VERSION 5.7 ;
  NOWIREEXTENSIONATPIN ON ;
  DIVIDERCHAR "/" ;
  BUSBITCHARS "[]" ;
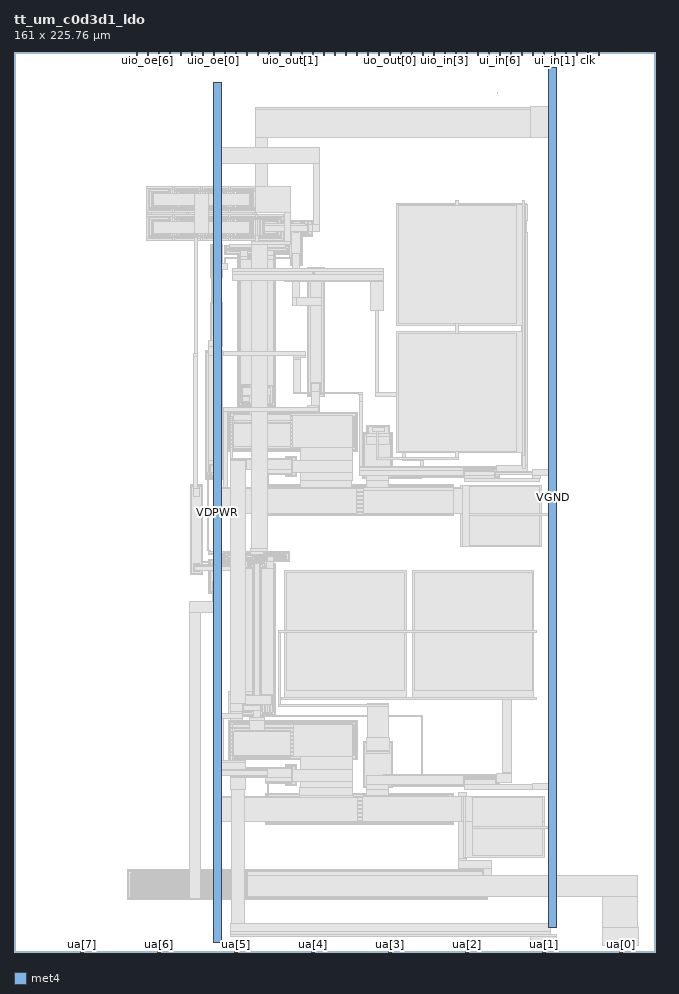
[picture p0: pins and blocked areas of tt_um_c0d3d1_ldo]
MACRO tt_um_c0d3d1_ldo
  CLASS BLOCK ;
  FOREIGN tt_um_c0d3d1_ldo ;
  ORIGIN 0.000 0.000 ;
  SIZE 161.000 BY 225.760 ;
  PIN clk
    DIRECTION INPUT ;
    USE SIGNAL ;
    PORT
      LAYER met4 ;
        RECT 143.830 224.760 144.130 225.760 ;
    END
  END clk
  PIN ena
    DIRECTION INPUT ;
    USE SIGNAL ;
    PORT
      LAYER met4 ;
        RECT 146.590 224.760 146.890 225.760 ;
    END
  END ena
  PIN rst_n
    DIRECTION INPUT ;
    USE SIGNAL ;
    PORT
      LAYER met4 ;
        RECT 141.070 224.760 141.370 225.760 ;
    END
  END rst_n
  PIN ua[0]
    DIRECTION INOUT ;
    USE SIGNAL ;
    ANTENNADIFFAREA 183.039993 ;
    PORT
      LAYER met4 ;
        RECT 151.810 0.000 152.710 1.000 ;
    END
  END ua[0]
  PIN ua[1]
    DIRECTION INOUT ;
    USE SIGNAL ;
    ANTENNAGATEAREA 738.719971 ;
    ANTENNADIFFAREA 1.740000 ;
    PORT
      LAYER met4 ;
        RECT 132.490 0.000 133.390 1.000 ;
    END
  END ua[1]
  PIN ua[2]
    DIRECTION INOUT ;
    USE SIGNAL ;
    PORT
      LAYER met4 ;
        RECT 113.170 0.000 114.070 1.000 ;
    END
  END ua[2]
  PIN ua[3]
    DIRECTION INOUT ;
    USE SIGNAL ;
    PORT
      LAYER met4 ;
        RECT 93.850 0.000 94.750 1.000 ;
    END
  END ua[3]
  PIN ua[4]
    DIRECTION INOUT ;
    USE SIGNAL ;
    PORT
      LAYER met4 ;
        RECT 74.530 0.000 75.430 1.000 ;
    END
  END ua[4]
  PIN ua[5]
    DIRECTION INOUT ;
    USE SIGNAL ;
    PORT
      LAYER met4 ;
        RECT 55.210 0.000 56.110 1.000 ;
    END
  END ua[5]
  PIN ua[6]
    DIRECTION INOUT ;
    USE SIGNAL ;
    PORT
      LAYER met4 ;
        RECT 35.890 0.000 36.790 1.000 ;
    END
  END ua[6]
  PIN ua[7]
    DIRECTION INOUT ;
    USE SIGNAL ;
    PORT
      LAYER met4 ;
        RECT 16.570 0.000 17.470 1.000 ;
    END
  END ua[7]
  PIN ui_in[0]
    DIRECTION INPUT ;
    USE SIGNAL ;
    PORT
      LAYER met4 ;
        RECT 138.310 224.760 138.610 225.760 ;
    END
  END ui_in[0]
  PIN ui_in[1]
    DIRECTION INPUT ;
    USE SIGNAL ;
    PORT
      LAYER met4 ;
        RECT 135.550 224.760 135.850 225.760 ;
    END
  END ui_in[1]
  PIN ui_in[2]
    DIRECTION INPUT ;
    USE SIGNAL ;
    PORT
      LAYER met4 ;
        RECT 132.790 224.760 133.090 225.760 ;
    END
  END ui_in[2]
  PIN ui_in[3]
    DIRECTION INPUT ;
    USE SIGNAL ;
    PORT
      LAYER met4 ;
        RECT 130.030 224.760 130.330 225.760 ;
    END
  END ui_in[3]
  PIN ui_in[4]
    DIRECTION INPUT ;
    USE SIGNAL ;
    PORT
      LAYER met4 ;
        RECT 127.270 224.760 127.570 225.760 ;
    END
  END ui_in[4]
  PIN ui_in[5]
    DIRECTION INPUT ;
    USE SIGNAL ;
    PORT
      LAYER met4 ;
        RECT 124.510 224.760 124.810 225.760 ;
    END
  END ui_in[5]
  PIN ui_in[6]
    DIRECTION INPUT ;
    USE SIGNAL ;
    PORT
      LAYER met4 ;
        RECT 121.750 224.760 122.050 225.760 ;
    END
  END ui_in[6]
  PIN ui_in[7]
    DIRECTION INPUT ;
    USE SIGNAL ;
    PORT
      LAYER met4 ;
        RECT 118.990 224.760 119.290 225.760 ;
    END
  END ui_in[7]
  PIN uio_in[0]
    DIRECTION INPUT ;
    USE SIGNAL ;
    PORT
      LAYER met4 ;
        RECT 116.230 224.760 116.530 225.760 ;
    END
  END uio_in[0]
  PIN uio_in[1]
    DIRECTION INPUT ;
    USE SIGNAL ;
    PORT
      LAYER met4 ;
        RECT 113.470 224.760 113.770 225.760 ;
    END
  END uio_in[1]
  PIN uio_in[2]
    DIRECTION INPUT ;
    USE SIGNAL ;
    PORT
      LAYER met4 ;
        RECT 110.710 224.760 111.010 225.760 ;
    END
  END uio_in[2]
  PIN uio_in[3]
    DIRECTION INPUT ;
    USE SIGNAL ;
    PORT
      LAYER met4 ;
        RECT 107.950 224.760 108.250 225.760 ;
    END
  END uio_in[3]
  PIN uio_in[4]
    DIRECTION INPUT ;
    USE SIGNAL ;
    PORT
      LAYER met4 ;
        RECT 105.190 224.760 105.490 225.760 ;
    END
  END uio_in[4]
  PIN uio_in[5]
    DIRECTION INPUT ;
    USE SIGNAL ;
    PORT
      LAYER met4 ;
        RECT 102.430 224.760 102.730 225.760 ;
    END
  END uio_in[5]
  PIN uio_in[6]
    DIRECTION INPUT ;
    USE SIGNAL ;
    PORT
      LAYER met4 ;
        RECT 99.670 224.760 99.970 225.760 ;
    END
  END uio_in[6]
  PIN uio_in[7]
    DIRECTION INPUT ;
    USE SIGNAL ;
    PORT
      LAYER met4 ;
        RECT 96.910 224.760 97.210 225.760 ;
    END
  END uio_in[7]
  PIN uio_oe[0]
    DIRECTION OUTPUT ;
    USE SIGNAL ;
    PORT
      LAYER met4 ;
        RECT 49.990 224.760 50.290 225.760 ;
    END
  END uio_oe[0]
  PIN uio_oe[1]
    DIRECTION OUTPUT ;
    USE SIGNAL ;
    PORT
      LAYER met4 ;
        RECT 47.230 224.760 47.530 225.760 ;
    END
  END uio_oe[1]
  PIN uio_oe[2]
    DIRECTION OUTPUT ;
    USE SIGNAL ;
    PORT
      LAYER met4 ;
        RECT 44.470 224.760 44.770 225.760 ;
    END
  END uio_oe[2]
  PIN uio_oe[3]
    DIRECTION OUTPUT ;
    USE SIGNAL ;
    PORT
      LAYER met4 ;
        RECT 41.710 224.760 42.010 225.760 ;
    END
  END uio_oe[3]
  PIN uio_oe[4]
    DIRECTION OUTPUT ;
    USE SIGNAL ;
    PORT
      LAYER met4 ;
        RECT 38.950 224.760 39.250 225.760 ;
    END
  END uio_oe[4]
  PIN uio_oe[5]
    DIRECTION OUTPUT ;
    USE SIGNAL ;
    PORT
      LAYER met4 ;
        RECT 36.190 224.760 36.490 225.760 ;
    END
  END uio_oe[5]
  PIN uio_oe[6]
    DIRECTION OUTPUT ;
    USE SIGNAL ;
    PORT
      LAYER met4 ;
        RECT 33.430 224.760 33.730 225.760 ;
    END
  END uio_oe[6]
  PIN uio_oe[7]
    DIRECTION OUTPUT ;
    USE SIGNAL ;
    PORT
      LAYER met4 ;
        RECT 30.670 224.760 30.970 225.760 ;
    END
  END uio_oe[7]
  PIN uio_out[0]
    DIRECTION OUTPUT ;
    USE SIGNAL ;
    PORT
      LAYER met4 ;
        RECT 72.070 224.760 72.370 225.760 ;
    END
  END uio_out[0]
  PIN uio_out[1]
    DIRECTION OUTPUT ;
    USE SIGNAL ;
    PORT
      LAYER met4 ;
        RECT 69.310 224.760 69.610 225.760 ;
    END
  END uio_out[1]
  PIN uio_out[2]
    DIRECTION OUTPUT ;
    USE SIGNAL ;
    PORT
      LAYER met4 ;
        RECT 66.550 224.760 66.850 225.760 ;
    END
  END uio_out[2]
  PIN uio_out[3]
    DIRECTION OUTPUT ;
    USE SIGNAL ;
    PORT
      LAYER met4 ;
        RECT 63.790 224.760 64.090 225.760 ;
    END
  END uio_out[3]
  PIN uio_out[4]
    DIRECTION OUTPUT ;
    USE SIGNAL ;
    PORT
      LAYER met4 ;
        RECT 61.030 224.760 61.330 225.760 ;
    END
  END uio_out[4]
  PIN uio_out[5]
    DIRECTION OUTPUT ;
    USE SIGNAL ;
    PORT
      LAYER met4 ;
        RECT 58.270 224.760 58.570 225.760 ;
    END
  END uio_out[5]
  PIN uio_out[6]
    DIRECTION OUTPUT ;
    USE SIGNAL ;
    PORT
      LAYER met4 ;
        RECT 55.510 224.760 55.810 225.760 ;
    END
  END uio_out[6]
  PIN uio_out[7]
    DIRECTION OUTPUT ;
    USE SIGNAL ;
    PORT
      LAYER met4 ;
        RECT 52.750 224.760 53.050 225.760 ;
    END
  END uio_out[7]
  PIN uo_out[0]
    DIRECTION OUTPUT ;
    USE SIGNAL ;
    PORT
      LAYER met4 ;
        RECT 94.150 224.760 94.450 225.760 ;
    END
  END uo_out[0]
  PIN uo_out[1]
    DIRECTION OUTPUT ;
    USE SIGNAL ;
    PORT
      LAYER met4 ;
        RECT 91.390 224.760 91.690 225.760 ;
    END
  END uo_out[1]
  PIN uo_out[2]
    DIRECTION OUTPUT ;
    USE SIGNAL ;
    PORT
      LAYER met4 ;
        RECT 88.630 224.760 88.930 225.760 ;
    END
  END uo_out[2]
  PIN uo_out[3]
    DIRECTION OUTPUT ;
    USE SIGNAL ;
    PORT
      LAYER met4 ;
        RECT 85.870 224.760 86.170 225.760 ;
    END
  END uo_out[3]
  PIN uo_out[4]
    DIRECTION OUTPUT ;
    USE SIGNAL ;
    PORT
      LAYER met4 ;
        RECT 83.110 224.760 83.410 225.760 ;
    END
  END uo_out[4]
  PIN uo_out[5]
    DIRECTION OUTPUT ;
    USE SIGNAL ;
    PORT
      LAYER met4 ;
        RECT 80.350 224.760 80.650 225.760 ;
    END
  END uo_out[5]
  PIN uo_out[6]
    DIRECTION OUTPUT ;
    USE SIGNAL ;
    PORT
      LAYER met4 ;
        RECT 77.590 224.760 77.890 225.760 ;
    END
  END uo_out[6]
  PIN uo_out[7]
    DIRECTION OUTPUT ;
    USE SIGNAL ;
    PORT
      LAYER met4 ;
        RECT 74.830 224.760 75.130 225.760 ;
    END
  END uo_out[7]
  PIN VDPWR
    DIRECTION INOUT ;
    USE POWER ;
    PORT
      LAYER met4 ;
        RECT 50.120 2.420 52.120 218.180 ;
    END
  END VDPWR
  PIN VGND
    DIRECTION INOUT ;
    USE GROUND ;
    PORT
      LAYER met4 ;
        RECT 134.120 6.130 136.120 221.890 ;
    END
  END VGND
  OBS
      LAYER pwell ;
        RECT 121.160 215.360 121.200 215.600 ;
        RECT 135.160 215.360 135.200 215.600 ;
        RECT 39.420 192.090 40.280 192.110 ;
        RECT 46.530 192.090 47.390 192.110 ;
        RECT 53.610 192.090 54.470 192.120 ;
        RECT 33.125 191.325 60.825 192.090 ;
        RECT 33.125 186.155 33.890 191.325 ;
        RECT 39.060 186.155 40.890 191.325 ;
        RECT 46.060 186.155 47.890 191.325 ;
        RECT 53.060 186.155 54.890 191.325 ;
        RECT 60.060 186.155 60.825 191.325 ;
        RECT 33.125 185.480 60.825 186.155 ;
        RECT 33.125 185.390 60.850 185.480 ;
        RECT 33.160 185.110 60.850 185.390 ;
        RECT 33.160 185.100 61.210 185.110 ;
        RECT 33.160 185.090 67.710 185.100 ;
        RECT 33.125 184.335 67.710 185.090 ;
        RECT 33.125 184.325 61.775 184.335 ;
        RECT 33.125 179.155 33.890 184.325 ;
        RECT 39.060 179.155 40.890 184.325 ;
        RECT 46.060 179.155 47.890 184.325 ;
        RECT 53.060 179.155 54.890 184.325 ;
        RECT 60.060 179.165 61.775 184.325 ;
        RECT 66.945 179.165 67.710 184.335 ;
        RECT 60.060 179.155 67.710 179.165 ;
        RECT 33.125 178.400 67.710 179.155 ;
        RECT 33.125 178.390 61.210 178.400 ;
        RECT 39.240 178.370 40.250 178.390 ;
        RECT 46.430 178.370 47.440 178.390 ;
        RECT 53.640 178.370 54.280 178.390 ;
        RECT 46.825 178.360 46.865 178.370 ;
        RECT 60.410 178.360 61.210 178.390 ;
        RECT 49.345 169.315 52.405 177.575 ;
        RECT 52.920 174.970 61.020 177.290 ;
        RECT 61.060 175.010 69.160 177.330 ;
      LAYER nwell ;
        RECT 56.175 174.910 60.435 174.935 ;
        RECT 56.175 174.865 61.720 174.910 ;
      LAYER pwell ;
        RECT 49.285 152.000 52.345 162.940 ;
      LAYER nwell ;
        RECT 48.035 118.645 52.295 150.825 ;
        RECT 56.175 136.755 65.690 174.865 ;
      LAYER pwell ;
        RECT 69.235 172.120 72.295 183.540 ;
      LAYER nwell ;
        RECT 72.615 179.590 74.935 183.570 ;
        RECT 73.605 139.435 77.865 171.615 ;
        RECT 60.170 136.690 65.690 136.755 ;
        RECT 61.430 136.685 65.690 136.690 ;
        RECT 53.885 125.655 86.065 135.395 ;
        RECT 68.170 119.165 70.850 124.345 ;
      LAYER pwell ;
        RECT 87.525 118.675 94.905 130.215 ;
        RECT 101.770 118.925 121.870 121.885 ;
        RECT 44.270 94.580 47.340 117.150 ;
      LAYER nwell ;
        RECT 63.015 109.455 110.195 117.175 ;
      LAYER pwell ;
        RECT 48.905 98.450 51.965 98.465 ;
        RECT 48.860 90.005 51.965 98.450 ;
        RECT 52.650 98.060 60.750 100.380 ;
        RECT 61.000 98.080 69.100 100.400 ;
      LAYER nwell ;
        RECT 56.195 97.520 60.455 97.525 ;
        RECT 56.195 97.455 61.640 97.520 ;
      LAYER pwell ;
        RECT 48.860 89.980 51.930 90.005 ;
      LAYER nwell ;
        RECT 56.195 59.345 65.710 97.455 ;
        RECT 59.160 59.290 65.710 59.345 ;
        RECT 61.450 59.275 65.710 59.290 ;
        RECT 59.160 57.985 63.230 58.000 ;
        RECT 53.905 48.245 86.085 57.985 ;
        RECT 68.190 41.755 70.870 46.935 ;
      LAYER pwell ;
        RECT 87.545 41.265 94.925 52.805 ;
        RECT 101.790 41.515 121.890 44.475 ;
      LAYER nwell ;
        RECT 63.035 32.045 110.215 39.765 ;
        RECT 28.490 13.210 118.670 20.630 ;
      LAYER li1 ;
        RECT 60.600 191.960 63.530 191.970 ;
        RECT 33.255 191.465 39.695 191.960 ;
        RECT 33.255 186.015 33.750 191.465 ;
        RECT 34.070 190.785 38.880 191.145 ;
        RECT 34.070 186.695 34.430 190.785 ;
        RECT 34.740 187.005 38.210 190.475 ;
        RECT 38.520 186.790 38.880 190.785 ;
        RECT 39.200 186.890 39.695 191.465 ;
        RECT 40.255 191.465 46.695 191.960 ;
        RECT 40.255 191.065 40.750 191.465 ;
        RECT 41.070 191.065 45.880 191.145 ;
        RECT 46.200 191.065 46.695 191.465 ;
        RECT 47.255 191.465 53.695 191.960 ;
        RECT 47.255 191.065 47.750 191.465 ;
        RECT 48.070 191.065 52.880 191.145 ;
        RECT 53.200 191.065 53.695 191.465 ;
        RECT 54.255 191.465 63.530 191.960 ;
        RECT 54.255 191.065 54.750 191.465 ;
        RECT 55.070 191.065 59.880 191.145 ;
        RECT 60.200 191.065 63.530 191.465 ;
        RECT 40.255 190.785 63.530 191.065 ;
        RECT 40.255 186.890 40.750 190.785 ;
        RECT 39.190 186.790 40.750 186.890 ;
        RECT 38.520 186.695 40.750 186.790 ;
        RECT 41.070 186.695 41.430 190.785 ;
        RECT 41.740 187.005 45.210 190.475 ;
        RECT 45.520 186.695 45.880 190.785 ;
        RECT 46.200 186.695 46.695 190.785 ;
        RECT 47.255 186.695 47.750 190.785 ;
        RECT 48.070 186.695 48.430 190.785 ;
        RECT 48.740 187.005 52.210 190.475 ;
        RECT 52.520 186.695 52.880 190.785 ;
        RECT 53.200 186.695 53.695 190.785 ;
        RECT 54.255 186.695 54.750 190.785 ;
        RECT 55.070 186.695 55.430 190.785 ;
        RECT 55.740 187.005 59.210 190.475 ;
        RECT 59.520 186.695 59.880 190.785 ;
        RECT 60.200 186.695 63.530 190.785 ;
        RECT 34.070 186.450 63.530 186.695 ;
        RECT 34.070 186.430 39.695 186.450 ;
        RECT 34.070 186.335 38.880 186.430 ;
        RECT 39.200 186.015 39.695 186.430 ;
        RECT 33.255 185.520 39.695 186.015 ;
        RECT 40.255 186.335 63.530 186.450 ;
        RECT 40.255 186.015 40.750 186.335 ;
        RECT 46.200 186.015 46.695 186.335 ;
        RECT 40.255 185.520 46.695 186.015 ;
        RECT 47.255 186.015 47.750 186.335 ;
        RECT 53.200 186.015 53.695 186.335 ;
        RECT 47.255 185.520 53.695 186.015 ;
        RECT 54.255 186.015 54.750 186.335 ;
        RECT 60.200 186.015 63.530 186.335 ;
        RECT 54.255 185.550 63.530 186.015 ;
        RECT 54.255 185.520 60.695 185.550 ;
        RECT 33.830 184.960 34.375 185.520 ;
        RECT 43.345 184.960 43.840 185.520 ;
        RECT 50.345 184.960 50.830 185.520 ;
        RECT 59.920 184.960 60.355 185.520 ;
        RECT 33.255 184.465 39.695 184.960 ;
        RECT 33.255 179.015 33.750 184.465 ;
        RECT 34.070 183.785 38.880 184.145 ;
        RECT 34.070 179.695 34.430 183.785 ;
        RECT 34.740 180.005 38.210 183.475 ;
        RECT 38.520 179.710 38.880 183.785 ;
        RECT 39.200 179.710 39.695 184.465 ;
        RECT 40.255 184.465 46.695 184.960 ;
        RECT 40.255 184.115 40.750 184.465 ;
        RECT 41.070 184.120 45.880 184.145 ;
        RECT 46.200 184.120 46.695 184.465 ;
        RECT 47.255 184.465 53.695 184.960 ;
        RECT 47.255 184.120 47.750 184.465 ;
        RECT 48.070 184.120 52.880 184.145 ;
        RECT 53.200 184.120 53.695 184.465 ;
        RECT 54.255 184.465 60.695 184.960 ;
        RECT 54.255 184.120 54.750 184.465 ;
        RECT 55.070 184.120 59.880 184.145 ;
        RECT 60.200 184.120 60.695 184.465 ;
        RECT 61.140 184.475 67.580 184.970 ;
        RECT 61.140 184.120 61.635 184.475 ;
        RECT 61.955 184.120 66.765 184.155 ;
        RECT 41.070 184.115 66.765 184.120 ;
        RECT 40.255 183.845 66.765 184.115 ;
        RECT 40.255 183.275 40.760 183.845 ;
        RECT 41.070 183.840 66.765 183.845 ;
        RECT 41.070 183.785 45.880 183.840 ;
        RECT 40.255 180.205 40.750 183.275 ;
        RECT 40.255 179.770 40.760 180.205 ;
        RECT 41.070 179.770 41.430 183.785 ;
        RECT 41.740 180.005 45.210 183.475 ;
        RECT 45.520 179.770 45.880 183.785 ;
        RECT 46.200 179.770 46.695 183.840 ;
        RECT 47.255 179.770 47.750 183.840 ;
        RECT 48.070 183.785 52.880 183.840 ;
        RECT 48.070 179.770 48.430 183.785 ;
        RECT 48.740 180.005 52.210 183.475 ;
        RECT 52.520 179.770 52.880 183.785 ;
        RECT 53.200 179.770 53.695 183.840 ;
        RECT 54.255 179.770 54.750 183.840 ;
        RECT 55.070 183.785 59.880 183.840 ;
        RECT 55.070 179.770 55.430 183.785 ;
        RECT 55.740 180.005 59.210 183.475 ;
        RECT 59.520 179.770 59.880 183.785 ;
        RECT 60.200 179.770 60.695 183.840 ;
        RECT 61.140 179.770 61.635 183.840 ;
        RECT 61.955 183.795 66.765 183.840 ;
        RECT 61.955 179.770 62.315 183.795 ;
        RECT 62.625 180.015 66.095 183.485 ;
        RECT 40.255 179.710 62.315 179.770 ;
        RECT 38.520 179.705 62.315 179.710 ;
        RECT 66.405 179.705 66.765 183.795 ;
        RECT 38.520 179.695 66.765 179.705 ;
        RECT 34.070 179.410 66.765 179.695 ;
        RECT 34.070 179.350 40.750 179.410 ;
        RECT 34.070 179.335 38.880 179.350 ;
        RECT 39.200 179.270 40.750 179.350 ;
        RECT 41.070 179.335 45.880 179.410 ;
        RECT 39.200 179.015 39.695 179.270 ;
        RECT 33.255 178.520 39.695 179.015 ;
        RECT 40.255 179.015 40.750 179.270 ;
        RECT 46.200 179.015 46.695 179.410 ;
        RECT 40.255 178.520 46.695 179.015 ;
        RECT 47.255 179.015 47.750 179.410 ;
        RECT 48.070 179.335 52.880 179.410 ;
        RECT 53.200 179.015 53.695 179.410 ;
        RECT 47.255 178.520 53.695 179.015 ;
        RECT 54.255 179.015 54.750 179.410 ;
        RECT 55.070 179.335 59.880 179.410 ;
        RECT 60.200 179.025 61.635 179.410 ;
        RECT 61.955 179.345 66.765 179.410 ;
        RECT 67.085 183.370 67.580 184.475 ;
        RECT 67.085 183.360 70.220 183.370 ;
        RECT 67.085 183.190 72.115 183.360 ;
        RECT 67.085 183.020 70.220 183.190 ;
        RECT 67.085 179.025 67.580 183.020 ;
        RECT 60.200 179.015 67.580 179.025 ;
        RECT 54.255 178.530 67.580 179.015 ;
        RECT 54.255 178.520 61.470 178.530 ;
        RECT 45.160 177.950 45.980 178.520 ;
        RECT 49.960 177.395 51.800 178.520 ;
        RECT 60.470 178.440 61.470 178.520 ;
        RECT 49.525 177.225 52.225 177.395 ;
        RECT 49.525 170.070 49.695 177.225 ;
        RECT 50.175 174.585 51.575 176.745 ;
        RECT 50.175 170.145 51.575 172.305 ;
        RECT 49.450 169.665 49.790 170.070 ;
        RECT 52.055 169.665 52.225 177.225 ;
        RECT 53.100 176.940 60.840 177.110 ;
        RECT 53.100 175.320 53.270 176.940 ;
        RECT 55.470 176.540 58.440 176.940 ;
        RECT 53.950 176.370 59.990 176.540 ;
        RECT 53.610 175.950 53.780 176.310 ;
        RECT 60.160 175.950 60.330 176.310 ;
        RECT 53.950 175.720 59.990 175.890 ;
        RECT 60.670 175.320 60.840 176.940 ;
        RECT 53.100 175.150 60.840 175.320 ;
        RECT 61.240 176.980 68.980 177.150 ;
        RECT 61.240 175.360 61.410 176.980 ;
        RECT 63.580 176.580 66.550 176.980 ;
        RECT 62.090 176.410 68.130 176.580 ;
        RECT 61.750 175.990 61.920 176.350 ;
        RECT 68.300 175.990 68.470 176.350 ;
        RECT 62.090 175.760 68.130 175.930 ;
        RECT 68.810 175.360 68.980 176.980 ;
        RECT 61.240 175.190 68.980 175.360 ;
        RECT 49.450 169.495 52.225 169.665 ;
        RECT 56.355 174.585 60.255 174.755 ;
        RECT 49.450 162.760 49.790 169.495 ;
        RECT 49.450 162.600 52.165 162.760 ;
        RECT 49.465 162.590 52.165 162.600 ;
        RECT 49.465 152.350 49.635 162.590 ;
        RECT 50.115 159.950 51.515 162.110 ;
        RECT 50.115 152.830 51.515 154.990 ;
        RECT 51.995 152.350 52.165 162.590 ;
        RECT 49.465 152.180 52.165 152.350 ;
        RECT 48.215 150.475 52.115 150.645 ;
        RECT 48.215 118.995 48.385 150.475 ;
        RECT 49.015 149.965 49.375 150.135 ;
        RECT 49.665 149.965 50.025 150.135 ;
        RECT 50.305 149.965 50.665 150.135 ;
        RECT 50.955 149.965 51.315 150.135 ;
        RECT 48.785 119.715 48.955 149.755 ;
        RECT 49.435 119.715 49.605 149.755 ;
        RECT 50.085 119.715 50.245 149.755 ;
        RECT 50.725 119.715 50.895 149.755 ;
        RECT 51.375 119.715 51.545 149.755 ;
        RECT 49.015 119.335 49.375 119.505 ;
        RECT 49.665 119.335 50.025 119.505 ;
        RECT 50.305 119.335 50.665 119.505 ;
        RECT 50.955 119.335 51.315 119.505 ;
        RECT 50.580 118.995 51.580 119.010 ;
        RECT 51.945 118.995 52.115 150.475 ;
        RECT 56.355 137.105 56.525 174.585 ;
        RECT 57.155 174.075 57.515 174.245 ;
        RECT 57.805 174.075 58.165 174.245 ;
        RECT 58.445 174.075 58.805 174.245 ;
        RECT 59.095 174.075 59.455 174.245 ;
        RECT 56.925 137.825 57.095 173.865 ;
        RECT 57.575 137.825 57.745 173.865 ;
        RECT 58.225 137.825 58.385 173.865 ;
        RECT 58.865 137.825 59.035 173.865 ;
        RECT 59.515 137.825 59.685 173.865 ;
        RECT 60.085 138.280 60.255 174.585 ;
        RECT 61.610 174.515 65.510 174.685 ;
        RECT 61.610 138.280 61.780 174.515 ;
        RECT 62.410 174.005 62.770 174.175 ;
        RECT 63.060 174.005 63.420 174.175 ;
        RECT 63.700 174.005 64.060 174.175 ;
        RECT 64.350 174.005 64.710 174.175 ;
        RECT 57.365 137.615 59.185 137.640 ;
        RECT 57.155 137.445 59.455 137.615 ;
        RECT 60.085 137.490 61.780 138.280 ;
        RECT 62.180 137.755 62.350 173.795 ;
        RECT 62.830 137.755 63.000 173.795 ;
        RECT 63.480 137.755 63.640 173.795 ;
        RECT 64.120 137.755 64.290 173.795 ;
        RECT 64.770 137.755 64.940 173.795 ;
        RECT 57.305 137.440 59.180 137.445 ;
        RECT 60.085 137.105 60.255 137.490 ;
        RECT 56.355 136.935 60.255 137.105 ;
        RECT 61.610 137.035 61.780 137.490 ;
        RECT 62.410 137.375 62.770 137.545 ;
        RECT 63.060 137.375 63.420 137.545 ;
        RECT 63.700 137.375 64.060 137.545 ;
        RECT 64.350 137.375 64.710 137.545 ;
        RECT 65.340 137.035 65.510 174.515 ;
        RECT 69.415 172.470 69.585 183.020 ;
        RECT 70.065 180.550 71.465 182.710 ;
        RECT 70.065 172.950 71.465 175.110 ;
        RECT 71.945 172.470 72.115 183.190 ;
        RECT 72.795 183.220 74.755 183.390 ;
        RECT 72.795 179.940 72.965 183.220 ;
        RECT 73.595 182.710 73.955 182.880 ;
        RECT 73.365 180.660 73.535 182.500 ;
        RECT 74.015 182.260 74.185 182.500 ;
        RECT 74.585 182.260 74.755 183.220 ;
        RECT 74.015 180.840 74.755 182.260 ;
        RECT 74.015 180.660 74.185 180.840 ;
        RECT 73.595 180.280 73.955 180.450 ;
        RECT 74.585 179.940 74.755 180.840 ;
        RECT 72.795 179.770 74.755 179.940 ;
        RECT 69.415 172.300 72.115 172.470 ;
        RECT 73.785 171.265 77.685 171.435 ;
        RECT 73.785 139.785 73.955 171.265 ;
        RECT 74.585 170.755 74.945 170.925 ;
        RECT 75.235 170.755 75.595 170.925 ;
        RECT 75.875 170.755 76.235 170.925 ;
        RECT 76.525 170.755 76.885 170.925 ;
        RECT 74.355 140.505 74.525 170.545 ;
        RECT 75.005 140.505 75.175 170.545 ;
        RECT 75.655 140.505 75.815 170.545 ;
        RECT 76.295 140.505 76.465 170.545 ;
        RECT 76.945 140.505 77.115 170.545 ;
        RECT 74.585 140.125 74.945 140.295 ;
        RECT 75.235 140.125 75.595 140.295 ;
        RECT 75.875 140.125 76.235 140.295 ;
        RECT 76.525 140.125 76.885 140.295 ;
        RECT 77.515 139.810 77.685 171.265 ;
        RECT 77.220 139.785 77.700 139.810 ;
        RECT 73.785 139.615 77.700 139.785 ;
        RECT 77.220 139.270 77.700 139.615 ;
        RECT 61.610 136.865 65.510 137.035 ;
        RECT 54.065 135.045 85.885 135.215 ;
        RECT 54.065 126.005 54.235 135.045 ;
        RECT 54.955 134.475 84.995 134.645 ;
        RECT 54.575 133.695 54.745 134.415 ;
        RECT 85.205 133.695 85.375 134.415 ;
        RECT 54.955 133.465 84.995 133.635 ;
        RECT 54.575 132.685 54.745 133.405 ;
        RECT 85.205 132.685 85.375 133.405 ;
        RECT 54.955 132.455 84.995 132.625 ;
        RECT 54.575 131.675 54.745 132.395 ;
        RECT 85.205 131.675 85.375 132.395 ;
        RECT 54.955 131.445 84.995 131.615 ;
        RECT 54.575 130.665 54.745 131.385 ;
        RECT 85.205 130.665 85.375 131.385 ;
        RECT 54.955 130.445 84.995 130.605 ;
        RECT 54.575 129.665 54.745 130.385 ;
        RECT 85.205 129.665 85.375 130.385 ;
        RECT 54.955 129.435 84.995 129.605 ;
        RECT 54.575 128.655 54.745 129.375 ;
        RECT 85.205 128.655 85.375 129.375 ;
        RECT 54.955 128.425 84.995 128.595 ;
        RECT 54.575 127.645 54.745 128.365 ;
        RECT 85.205 127.645 85.375 128.365 ;
        RECT 54.955 127.415 84.995 127.585 ;
        RECT 54.575 126.635 54.745 127.355 ;
        RECT 85.205 126.635 85.375 127.355 ;
        RECT 54.955 126.405 84.995 126.575 ;
        RECT 85.715 126.005 85.885 135.045 ;
        RECT 54.065 125.835 85.885 126.005 ;
        RECT 87.705 129.865 94.725 130.035 ;
        RECT 71.810 125.580 84.800 125.835 ;
        RECT 68.350 123.995 70.670 124.165 ;
        RECT 68.350 119.515 68.520 123.995 ;
        RECT 69.150 123.485 69.870 123.655 ;
        RECT 68.920 120.235 69.090 123.275 ;
        RECT 69.930 123.240 70.100 123.275 ;
        RECT 70.500 123.240 70.670 123.995 ;
        RECT 69.930 120.410 70.670 123.240 ;
        RECT 69.930 120.235 70.100 120.410 ;
        RECT 69.150 119.855 69.870 120.025 ;
        RECT 70.500 119.515 70.670 120.410 ;
        RECT 68.350 119.345 70.670 119.515 ;
        RECT 48.215 118.825 52.115 118.995 ;
        RECT 87.705 119.025 87.875 129.865 ;
        RECT 88.355 127.225 94.075 129.385 ;
        RECT 88.355 119.505 94.075 121.665 ;
        RECT 94.555 119.260 94.725 129.865 ;
        RECT 101.950 121.535 121.690 121.705 ;
        RECT 101.950 119.275 102.120 121.535 ;
        RECT 102.800 120.965 120.840 121.135 ;
        RECT 102.460 120.545 102.630 120.905 ;
        RECT 121.010 120.545 121.180 120.905 ;
        RECT 102.800 120.325 120.840 120.485 ;
        RECT 102.460 119.905 102.630 120.265 ;
        RECT 121.010 119.905 121.180 120.265 ;
        RECT 102.800 119.675 120.840 119.845 ;
        RECT 113.100 119.275 120.580 119.340 ;
        RECT 121.520 119.275 121.690 121.535 ;
        RECT 101.950 119.260 121.690 119.275 ;
        RECT 94.540 119.105 121.690 119.260 ;
        RECT 94.540 119.025 102.250 119.105 ;
        RECT 87.705 118.870 102.250 119.025 ;
        RECT 87.705 118.855 94.725 118.870 ;
        RECT 113.100 118.850 120.580 119.105 ;
        RECT 50.580 118.390 51.580 118.825 ;
        RECT 71.840 116.995 84.680 117.280 ;
        RECT 44.455 116.795 47.155 116.965 ;
        RECT 44.455 94.935 44.625 116.795 ;
        RECT 45.200 116.315 46.500 116.795 ;
        RECT 45.105 114.155 46.505 116.315 ;
        RECT 46.985 97.850 47.155 116.795 ;
        RECT 63.195 116.825 110.015 116.995 ;
        RECT 63.195 109.805 63.365 116.825 ;
        RECT 64.085 116.255 109.125 116.425 ;
        RECT 63.705 115.475 63.875 116.195 ;
        RECT 109.335 115.475 109.505 116.195 ;
        RECT 64.085 115.245 109.125 115.415 ;
        RECT 63.705 114.465 63.875 115.185 ;
        RECT 109.335 114.465 109.505 115.185 ;
        RECT 64.085 114.235 109.125 114.405 ;
        RECT 63.705 113.455 63.875 114.175 ;
        RECT 109.335 113.455 109.505 114.175 ;
        RECT 64.085 113.235 109.125 113.395 ;
        RECT 63.705 112.455 63.875 113.175 ;
        RECT 109.335 112.455 109.505 113.175 ;
        RECT 64.085 112.225 109.125 112.395 ;
        RECT 63.705 111.445 63.875 112.165 ;
        RECT 109.335 111.445 109.505 112.165 ;
        RECT 64.085 111.215 109.125 111.385 ;
        RECT 63.705 110.435 63.875 111.155 ;
        RECT 109.335 110.435 109.505 111.155 ;
        RECT 64.085 110.205 109.125 110.375 ;
        RECT 109.845 109.805 110.015 116.825 ;
        RECT 63.195 109.635 110.015 109.805 ;
        RECT 52.830 100.030 60.570 100.200 ;
        RECT 52.830 98.410 53.000 100.030 ;
        RECT 56.290 99.630 56.730 100.030 ;
        RECT 53.680 99.460 59.720 99.630 ;
        RECT 56.290 99.430 56.730 99.460 ;
        RECT 53.340 99.040 53.510 99.400 ;
        RECT 59.890 99.040 60.060 99.400 ;
        RECT 53.680 98.810 59.720 98.980 ;
        RECT 60.400 98.410 60.570 100.030 ;
        RECT 49.085 98.115 51.785 98.285 ;
        RECT 52.830 98.240 60.570 98.410 ;
        RECT 61.180 100.050 68.920 100.220 ;
        RECT 61.180 98.430 61.350 100.050 ;
        RECT 64.540 99.650 64.980 100.050 ;
        RECT 62.030 99.480 68.070 99.650 ;
        RECT 61.690 99.060 61.860 99.420 ;
        RECT 68.240 99.060 68.410 99.420 ;
        RECT 62.030 98.830 68.070 99.000 ;
        RECT 68.750 98.430 68.920 100.050 ;
        RECT 61.180 98.260 68.920 98.430 ;
        RECT 49.085 97.850 49.255 98.115 ;
        RECT 46.985 97.600 49.280 97.850 ;
        RECT 45.105 95.415 46.505 97.575 ;
        RECT 46.985 94.935 47.155 97.600 ;
        RECT 44.455 94.765 47.155 94.935 ;
        RECT 49.085 90.355 49.255 97.600 ;
        RECT 49.735 95.475 51.135 97.635 ;
        RECT 49.735 90.835 51.135 92.995 ;
        RECT 51.615 90.355 51.785 98.115 ;
        RECT 49.085 90.185 51.785 90.355 ;
        RECT 56.375 97.175 60.275 97.345 ;
        RECT 56.375 59.695 56.545 97.175 ;
        RECT 57.175 96.665 57.535 96.835 ;
        RECT 57.825 96.665 58.185 96.835 ;
        RECT 58.465 96.665 58.825 96.835 ;
        RECT 59.115 96.665 59.475 96.835 ;
        RECT 56.945 60.415 57.115 96.455 ;
        RECT 57.595 60.415 57.765 96.455 ;
        RECT 58.245 60.415 58.405 96.455 ;
        RECT 58.885 60.415 59.055 96.455 ;
        RECT 59.535 60.415 59.705 96.455 ;
        RECT 60.105 61.440 60.275 97.175 ;
        RECT 61.630 97.105 65.530 97.275 ;
        RECT 61.630 61.440 61.800 97.105 ;
        RECT 62.430 96.595 62.790 96.765 ;
        RECT 63.080 96.595 63.440 96.765 ;
        RECT 63.720 96.595 64.080 96.765 ;
        RECT 64.370 96.595 64.730 96.765 ;
        RECT 60.105 60.450 61.800 61.440 ;
        RECT 57.385 60.205 59.205 60.230 ;
        RECT 57.175 60.035 59.475 60.205 ;
        RECT 57.325 60.030 59.200 60.035 ;
        RECT 60.105 59.695 60.275 60.450 ;
        RECT 56.375 59.525 60.275 59.695 ;
        RECT 61.630 59.625 61.800 60.450 ;
        RECT 62.200 60.345 62.370 96.385 ;
        RECT 62.850 60.345 63.020 96.385 ;
        RECT 63.500 60.345 63.660 96.385 ;
        RECT 64.140 60.345 64.310 96.385 ;
        RECT 64.790 60.345 64.960 96.385 ;
        RECT 62.430 59.965 62.790 60.135 ;
        RECT 63.080 59.965 63.440 60.135 ;
        RECT 63.720 59.965 64.080 60.135 ;
        RECT 64.370 59.965 64.730 60.135 ;
        RECT 65.360 59.625 65.530 97.105 ;
        RECT 61.630 59.455 65.530 59.625 ;
        RECT 54.085 57.635 85.905 57.805 ;
        RECT 54.085 48.595 54.255 57.635 ;
        RECT 54.975 57.065 85.015 57.235 ;
        RECT 54.595 56.285 54.765 57.005 ;
        RECT 85.225 56.285 85.395 57.005 ;
        RECT 54.975 56.055 85.015 56.225 ;
        RECT 54.595 55.275 54.765 55.995 ;
        RECT 85.225 55.275 85.395 55.995 ;
        RECT 54.975 55.045 85.015 55.215 ;
        RECT 54.595 54.265 54.765 54.985 ;
        RECT 85.225 54.265 85.395 54.985 ;
        RECT 54.975 54.035 85.015 54.205 ;
        RECT 54.595 53.255 54.765 53.975 ;
        RECT 85.225 53.255 85.395 53.975 ;
        RECT 54.975 53.035 85.015 53.195 ;
        RECT 54.595 52.255 54.765 52.975 ;
        RECT 85.225 52.255 85.395 52.975 ;
        RECT 54.975 52.025 85.015 52.195 ;
        RECT 54.595 51.245 54.765 51.965 ;
        RECT 85.225 51.245 85.395 51.965 ;
        RECT 54.975 51.015 85.015 51.185 ;
        RECT 54.595 50.235 54.765 50.955 ;
        RECT 85.225 50.235 85.395 50.955 ;
        RECT 54.975 50.005 85.015 50.175 ;
        RECT 54.595 49.225 54.765 49.945 ;
        RECT 85.225 49.225 85.395 49.945 ;
        RECT 54.975 48.995 85.015 49.165 ;
        RECT 85.735 48.595 85.905 57.635 ;
        RECT 54.085 48.425 85.905 48.595 ;
        RECT 87.725 52.455 94.745 52.625 ;
        RECT 71.810 48.010 84.810 48.425 ;
        RECT 68.370 46.585 70.690 46.755 ;
        RECT 68.370 42.105 68.540 46.585 ;
        RECT 69.170 46.075 69.890 46.245 ;
        RECT 68.940 42.825 69.110 45.865 ;
        RECT 69.950 45.830 70.120 45.865 ;
        RECT 70.520 45.830 70.690 46.585 ;
        RECT 69.950 43.000 70.690 45.830 ;
        RECT 69.950 42.825 70.120 43.000 ;
        RECT 69.170 42.445 69.890 42.615 ;
        RECT 70.520 42.105 70.690 43.000 ;
        RECT 68.370 41.935 70.690 42.105 ;
        RECT 87.725 41.615 87.895 52.455 ;
        RECT 88.375 49.815 94.095 51.975 ;
        RECT 88.375 42.095 94.095 44.255 ;
        RECT 94.575 41.860 94.745 52.455 ;
        RECT 101.970 44.125 121.710 44.295 ;
        RECT 101.970 41.865 102.140 44.125 ;
        RECT 102.820 43.555 120.860 43.725 ;
        RECT 102.480 43.135 102.650 43.495 ;
        RECT 121.030 43.135 121.200 43.495 ;
        RECT 102.820 42.915 120.860 43.075 ;
        RECT 102.480 42.495 102.650 42.855 ;
        RECT 121.030 42.495 121.200 42.855 ;
        RECT 102.820 42.265 120.860 42.435 ;
        RECT 113.160 41.865 120.910 41.890 ;
        RECT 121.540 41.865 121.710 44.125 ;
        RECT 101.970 41.860 121.710 41.865 ;
        RECT 94.575 41.695 121.710 41.860 ;
        RECT 94.575 41.615 102.400 41.695 ;
        RECT 87.725 41.470 102.400 41.615 ;
        RECT 87.725 41.445 94.745 41.470 ;
        RECT 113.160 41.440 120.910 41.695 ;
        RECT 71.830 39.585 84.790 39.920 ;
        RECT 63.215 39.415 110.035 39.585 ;
        RECT 63.215 32.395 63.385 39.415 ;
        RECT 71.830 39.410 84.790 39.415 ;
        RECT 71.860 39.390 84.660 39.410 ;
        RECT 64.105 38.845 109.145 39.015 ;
        RECT 63.725 38.065 63.895 38.785 ;
        RECT 109.355 38.065 109.525 38.785 ;
        RECT 64.105 37.835 109.145 38.005 ;
        RECT 63.725 37.055 63.895 37.775 ;
        RECT 109.355 37.055 109.525 37.775 ;
        RECT 64.105 36.825 109.145 36.995 ;
        RECT 63.725 36.045 63.895 36.765 ;
        RECT 109.355 36.045 109.525 36.765 ;
        RECT 64.105 35.825 109.145 35.985 ;
        RECT 63.725 35.045 63.895 35.765 ;
        RECT 109.355 35.045 109.525 35.765 ;
        RECT 64.105 34.815 109.145 34.985 ;
        RECT 63.725 34.035 63.895 34.755 ;
        RECT 109.355 34.035 109.525 34.755 ;
        RECT 64.105 33.805 109.145 33.975 ;
        RECT 63.725 33.025 63.895 33.745 ;
        RECT 109.355 33.025 109.525 33.745 ;
        RECT 64.105 32.795 109.145 32.965 ;
        RECT 109.865 32.395 110.035 39.415 ;
        RECT 63.215 32.225 110.035 32.395 ;
        RECT 50.100 20.450 52.100 20.600 ;
        RECT 28.670 20.280 118.490 20.450 ;
        RECT 28.670 13.560 28.840 20.280 ;
        RECT 50.100 20.180 52.100 20.280 ;
        RECT 29.180 14.040 29.350 19.800 ;
        RECT 29.560 19.710 117.600 19.880 ;
        RECT 29.560 19.230 117.600 19.400 ;
        RECT 29.560 18.750 117.600 18.920 ;
        RECT 29.560 18.270 117.600 18.440 ;
        RECT 29.560 17.790 117.600 17.960 ;
        RECT 29.560 17.310 117.600 17.480 ;
        RECT 29.560 16.840 117.600 17.000 ;
        RECT 29.560 16.360 117.600 16.530 ;
        RECT 29.560 15.880 117.600 16.050 ;
        RECT 29.560 15.400 117.600 15.570 ;
        RECT 29.560 14.920 117.600 15.090 ;
        RECT 29.560 14.440 117.600 14.610 ;
        RECT 29.560 13.960 117.600 14.130 ;
        RECT 117.810 14.040 117.980 19.800 ;
        RECT 118.320 13.560 118.490 20.280 ;
        RECT 28.670 13.390 118.490 13.560 ;
      LAYER met1 ;
        RECT 60.700 211.430 132.290 211.900 ;
        RECT 60.620 204.380 132.290 211.430 ;
        RECT 34.950 190.250 38.000 190.265 ;
        RECT 41.950 190.250 45.000 190.265 ;
        RECT 48.950 190.250 52.000 190.265 ;
        RECT 55.950 190.250 59.000 190.265 ;
        RECT 34.950 187.230 59.000 190.250 ;
        RECT 34.950 187.215 38.000 187.230 ;
        RECT 41.950 187.215 45.000 187.230 ;
        RECT 48.950 187.215 52.000 187.230 ;
        RECT 55.950 187.215 59.000 187.230 ;
        RECT 60.620 185.610 63.550 204.380 ;
        RECT 127.240 187.540 128.520 187.710 ;
        RECT 127.240 183.525 128.920 187.540 ;
        RECT 34.950 183.215 38.000 183.265 ;
        RECT 41.950 183.215 45.000 183.265 ;
        RECT 48.950 183.215 52.000 183.265 ;
        RECT 55.950 183.215 59.000 183.265 ;
        RECT 34.915 180.215 59.000 183.215 ;
        RECT 62.835 182.615 65.915 183.275 ;
        RECT 73.590 182.680 73.960 182.910 ;
        RECT 70.115 182.615 71.415 182.680 ;
        RECT 62.835 182.360 73.180 182.615 ;
        RECT 73.335 182.360 73.565 182.480 ;
        RECT 73.985 182.380 74.215 182.480 ;
        RECT 62.835 180.680 73.580 182.360 ;
        RECT 73.985 180.790 76.600 182.380 ;
        RECT 73.985 180.680 74.215 180.790 ;
        RECT 62.835 180.225 65.915 180.680 ;
        RECT 34.915 180.195 58.965 180.215 ;
        RECT 62.935 180.205 65.915 180.225 ;
        RECT 45.160 150.120 45.990 179.160 ;
        RECT 60.510 177.500 61.370 179.620 ;
        RECT 50.130 174.600 51.670 177.480 ;
        RECT 58.780 177.470 62.810 177.500 ;
        RECT 53.980 176.800 68.090 177.470 ;
        RECT 53.980 176.710 61.690 176.800 ;
        RECT 53.980 176.570 59.940 176.710 ;
        RECT 62.260 176.610 68.090 176.800 ;
        RECT 53.430 175.940 53.810 176.390 ;
        RECT 53.970 176.340 59.970 176.570 ;
        RECT 62.110 176.380 68.110 176.610 ;
        RECT 60.170 176.360 60.510 176.380 ;
        RECT 61.570 176.360 61.950 176.380 ;
        RECT 60.170 176.290 61.950 176.360 ;
        RECT 60.130 175.990 61.950 176.290 ;
        RECT 68.260 175.990 68.640 176.400 ;
        RECT 60.130 175.970 68.640 175.990 ;
        RECT 60.170 175.950 68.640 175.970 ;
        RECT 60.170 175.920 68.630 175.950 ;
        RECT 53.970 175.690 59.970 175.920 ;
        RECT 60.170 175.910 60.510 175.920 ;
        RECT 61.770 175.800 68.630 175.920 ;
        RECT 56.770 175.360 58.660 175.690 ;
        RECT 62.020 175.570 68.630 175.800 ;
        RECT 63.360 174.740 65.100 175.570 ;
        RECT 69.210 174.280 69.580 180.680 ;
        RECT 70.115 180.570 71.415 180.680 ;
        RECT 73.085 180.480 73.375 180.680 ;
        RECT 127.240 180.505 128.485 183.525 ;
        RECT 73.085 180.190 73.960 180.480 ;
        RECT 52.695 174.270 55.730 174.280 ;
        RECT 57.160 174.270 59.480 174.280 ;
        RECT 52.695 174.040 59.480 174.270 ;
        RECT 52.695 174.030 59.460 174.040 ;
        RECT 50.670 172.700 51.220 172.730 ;
        RECT 50.160 172.680 51.490 172.700 ;
        RECT 52.695 172.680 52.945 174.030 ;
        RECT 62.370 173.920 69.580 174.280 ;
        RECT 56.895 173.780 57.125 173.845 ;
        RECT 50.090 171.260 53.540 172.680 ;
        RECT 50.160 170.175 51.525 171.260 ;
        RECT 50.160 159.930 51.490 170.175 ;
        RECT 50.165 152.860 51.465 154.970 ;
        RECT 50.520 151.860 51.330 152.860 ;
        RECT 52.520 150.200 55.400 150.550 ;
        RECT 49.030 150.170 55.400 150.200 ;
        RECT 45.090 149.380 45.990 150.120 ;
        RECT 48.990 149.920 55.400 150.170 ;
        RECT 48.755 149.690 48.985 149.735 ;
        RECT 45.090 116.285 45.950 149.380 ;
        RECT 48.720 122.430 49.090 149.690 ;
        RECT 48.755 120.300 48.985 122.430 ;
        RECT 49.405 122.030 49.635 149.735 ;
        RECT 50.055 149.670 50.275 149.735 ;
        RECT 49.990 122.420 50.380 149.670 ;
        RECT 49.310 120.350 49.820 122.030 ;
        RECT 48.580 119.735 48.985 120.300 ;
        RECT 49.405 119.735 49.635 120.350 ;
        RECT 50.055 119.735 50.275 122.420 ;
        RECT 50.695 122.040 50.925 149.735 ;
        RECT 51.345 149.620 51.575 149.735 ;
        RECT 51.190 123.320 51.600 149.620 ;
        RECT 52.520 149.550 55.400 149.920 ;
        RECT 56.800 142.050 57.230 173.780 ;
        RECT 56.895 137.845 57.125 142.050 ;
        RECT 57.545 141.670 57.775 173.845 ;
        RECT 58.195 173.840 58.415 173.845 ;
        RECT 58.050 142.110 58.480 173.840 ;
        RECT 57.430 139.640 57.890 141.670 ;
        RECT 57.545 139.400 57.775 139.640 ;
        RECT 57.350 139.250 57.860 139.400 ;
        RECT 57.420 137.910 57.820 139.250 ;
        RECT 57.545 137.845 57.775 137.910 ;
        RECT 58.195 137.845 58.415 142.110 ;
        RECT 58.835 141.670 59.065 173.845 ;
        RECT 59.485 173.740 59.715 173.845 ;
        RECT 62.150 173.740 62.380 173.775 ;
        RECT 59.390 142.270 59.790 173.740 ;
        RECT 58.690 139.640 59.150 141.670 ;
        RECT 58.835 137.845 59.065 139.640 ;
        RECT 59.485 137.845 59.715 142.270 ;
        RECT 62.130 142.010 62.500 173.740 ;
        RECT 57.175 137.640 57.495 137.645 ;
        RECT 57.825 137.640 58.145 137.645 ;
        RECT 58.465 137.640 58.785 137.645 ;
        RECT 59.115 137.640 59.435 137.645 ;
        RECT 57.160 137.420 59.460 137.640 ;
        RECT 60.090 137.470 61.770 138.260 ;
        RECT 62.150 137.775 62.380 142.010 ;
        RECT 62.800 141.740 63.030 173.775 ;
        RECT 63.450 173.740 63.670 173.775 ;
        RECT 63.390 142.010 63.820 173.740 ;
        RECT 62.650 139.580 63.200 141.740 ;
        RECT 62.800 137.775 63.030 139.580 ;
        RECT 63.450 137.775 63.670 142.010 ;
        RECT 64.090 141.730 64.320 173.775 ;
        RECT 64.740 173.740 64.970 173.775 ;
        RECT 64.600 142.010 65.030 173.740 ;
        RECT 69.970 164.190 71.510 175.190 ;
        RECT 74.605 170.930 74.925 170.955 ;
        RECT 75.255 170.930 75.575 170.955 ;
        RECT 75.895 170.930 76.215 170.955 ;
        RECT 76.545 170.930 76.865 170.955 ;
        RECT 74.600 170.700 76.930 170.930 ;
        RECT 74.325 169.890 74.555 170.525 ;
        RECT 69.970 162.160 71.680 164.190 ;
        RECT 70.920 162.120 71.680 162.160 ;
        RECT 69.310 149.610 73.170 150.590 ;
        RECT 70.170 149.210 73.150 149.610 ;
        RECT 70.170 148.670 71.880 149.210 ;
        RECT 63.950 139.610 64.450 141.730 ;
        RECT 64.090 137.775 64.320 139.610 ;
        RECT 64.740 137.775 64.970 142.010 ;
        RECT 70.170 140.290 71.870 148.670 ;
        RECT 74.270 142.870 74.650 169.890 ;
        RECT 74.325 140.525 74.555 142.870 ;
        RECT 74.975 142.620 75.205 170.525 ;
        RECT 75.625 169.900 75.845 170.525 ;
        RECT 75.560 142.880 75.940 169.900 ;
        RECT 74.790 140.520 75.370 142.620 ;
        RECT 75.625 140.525 75.845 142.880 ;
        RECT 76.265 142.620 76.495 170.525 ;
        RECT 76.915 169.900 77.145 170.525 ;
        RECT 76.750 142.870 77.240 169.900 ;
        RECT 89.540 160.950 92.710 171.550 ;
        RECT 76.180 140.540 76.680 142.620 ;
        RECT 76.265 140.525 76.495 140.540 ;
        RECT 76.915 140.525 77.145 142.870 ;
        RECT 74.605 140.290 74.925 140.325 ;
        RECT 75.255 140.290 75.575 140.325 ;
        RECT 75.895 140.290 76.215 140.325 ;
        RECT 76.545 140.310 76.865 140.325 ;
        RECT 86.440 140.310 87.380 140.450 ;
        RECT 76.545 140.290 87.380 140.310 ;
        RECT 70.170 140.240 73.150 140.290 ;
        RECT 74.605 140.240 87.380 140.290 ;
        RECT 70.170 140.070 87.380 140.240 ;
        RECT 74.610 140.050 87.380 140.070 ;
        RECT 86.440 139.970 87.380 140.050 ;
        RECT 90.720 140.230 91.535 160.950 ;
        RECT 76.040 139.820 77.190 139.830 ;
        RECT 76.040 139.260 77.700 139.820 ;
        RECT 90.720 139.415 98.205 140.230 ;
        RECT 76.550 139.250 77.700 139.260 ;
        RECT 62.430 137.550 62.750 137.575 ;
        RECT 63.080 137.550 63.400 137.575 ;
        RECT 63.720 137.550 64.040 137.575 ;
        RECT 64.370 137.550 64.690 137.575 ;
        RECT 57.175 137.415 57.495 137.420 ;
        RECT 57.825 137.415 58.145 137.420 ;
        RECT 58.465 137.415 58.785 137.420 ;
        RECT 59.115 137.415 59.435 137.420 ;
        RECT 62.420 137.330 64.730 137.550 ;
        RECT 59.170 135.220 62.820 136.210 ;
        RECT 55.170 134.675 69.320 134.780 ;
        RECT 54.975 134.445 84.975 134.675 ;
        RECT 54.390 134.395 54.770 134.400 ;
        RECT 54.390 133.715 54.775 134.395 ;
        RECT 55.170 134.210 69.320 134.445 ;
        RECT 54.390 133.385 54.770 133.715 ;
        RECT 69.960 133.665 84.830 133.930 ;
        RECT 85.175 133.715 85.405 134.395 ;
        RECT 54.975 133.435 84.975 133.665 ;
        RECT 54.390 132.705 54.775 133.385 ;
        RECT 69.960 133.200 84.830 133.435 ;
        RECT 54.390 132.375 54.770 132.705 ;
        RECT 55.170 132.655 69.320 132.900 ;
        RECT 85.175 132.705 85.405 133.385 ;
        RECT 54.975 132.425 84.975 132.655 ;
        RECT 54.390 131.695 54.775 132.375 ;
        RECT 55.170 132.170 69.320 132.425 ;
        RECT 54.390 131.365 54.770 131.695 ;
        RECT 70.000 131.645 84.790 132.000 ;
        RECT 85.175 131.695 85.405 132.375 ;
        RECT 54.975 131.415 84.975 131.645 ;
        RECT 54.390 130.685 54.775 131.365 ;
        RECT 70.000 131.130 84.790 131.415 ;
        RECT 54.390 130.365 54.770 130.685 ;
        RECT 55.190 130.635 69.340 130.880 ;
        RECT 85.175 130.685 85.405 131.365 ;
        RECT 54.975 130.415 84.975 130.635 ;
        RECT 54.390 129.685 54.775 130.365 ;
        RECT 55.190 130.150 69.340 130.415 ;
        RECT 54.390 129.355 54.770 129.685 ;
        RECT 69.980 129.635 84.810 129.980 ;
        RECT 85.175 129.685 85.405 130.365 ;
        RECT 54.975 129.405 84.975 129.635 ;
        RECT 54.390 128.675 54.775 129.355 ;
        RECT 69.980 129.160 84.810 129.405 ;
        RECT 54.390 128.345 54.770 128.675 ;
        RECT 55.170 128.625 69.320 128.840 ;
        RECT 85.175 128.675 85.405 129.355 ;
        RECT 88.480 129.325 94.100 132.030 ;
        RECT 54.975 128.395 84.975 128.625 ;
        RECT 54.390 127.665 54.775 128.345 ;
        RECT 55.170 128.110 69.320 128.395 ;
        RECT 54.390 127.335 54.770 127.665 ;
        RECT 70.000 127.615 84.830 127.860 ;
        RECT 85.175 127.665 85.405 128.345 ;
        RECT 54.975 127.385 84.975 127.615 ;
        RECT 88.375 127.400 94.100 129.325 ;
        RECT 54.390 126.655 54.775 127.335 ;
        RECT 70.000 127.040 84.830 127.385 ;
        RECT 54.390 123.740 54.770 126.655 ;
        RECT 55.190 126.605 69.340 126.970 ;
        RECT 85.175 126.655 85.405 127.335 ;
        RECT 88.375 127.285 94.055 127.400 ;
        RECT 54.975 126.375 84.975 126.605 ;
        RECT 55.190 126.240 69.340 126.375 ;
        RECT 71.810 125.580 84.800 125.990 ;
        RECT 97.400 124.160 98.190 139.415 ;
        RECT 63.040 123.740 69.560 123.760 ;
        RECT 54.390 123.685 69.560 123.740 ;
        RECT 54.390 123.455 69.850 123.685 ;
        RECT 50.520 120.360 51.060 122.040 ;
        RECT 50.695 119.735 50.925 120.360 ;
        RECT 51.345 119.735 51.575 123.320 ;
        RECT 54.390 121.130 69.560 123.455 ;
        RECT 97.400 123.400 102.640 124.160 ;
        RECT 97.400 123.385 98.190 123.400 ;
        RECT 69.920 123.255 70.450 123.270 ;
        RECT 54.390 121.090 54.770 121.130 ;
        RECT 63.040 120.055 69.560 121.130 ;
        RECT 69.900 120.270 70.450 123.255 ;
        RECT 69.900 120.255 70.130 120.270 ;
        RECT 63.040 119.825 69.850 120.055 ;
        RECT 63.040 119.790 69.560 119.825 ;
        RECT 45.090 114.350 46.455 116.285 ;
        RECT 45.155 114.185 46.455 114.350 ;
        RECT 48.580 100.680 48.850 119.735 ;
        RECT 49.030 119.290 51.330 119.540 ;
        RECT 50.580 118.390 51.580 119.010 ;
        RECT 63.500 110.350 63.930 119.790 ;
        RECT 88.375 119.565 94.055 121.605 ;
        RECT 101.880 120.910 102.640 123.400 ;
        RECT 127.240 122.130 128.920 180.505 ;
        RECT 102.980 121.165 112.730 121.480 ;
        RECT 102.820 120.935 120.820 121.165 ;
        RECT 103.020 120.930 112.740 120.935 ;
        RECT 101.880 119.890 102.680 120.910 ;
        RECT 103.030 120.830 112.740 120.930 ;
        RECT 113.090 120.515 120.590 120.680 ;
        RECT 102.820 120.295 120.820 120.515 ;
        RECT 113.090 120.070 120.590 120.295 ;
        RECT 101.880 119.780 102.640 119.890 ;
        RECT 102.860 119.875 112.720 119.960 ;
        RECT 120.960 119.880 128.920 122.130 ;
        RECT 102.820 119.645 120.820 119.875 ;
        RECT 120.960 119.820 128.070 119.880 ;
        RECT 120.970 119.790 121.460 119.820 ;
        RECT 102.860 119.480 112.720 119.645 ;
        RECT 113.090 118.870 120.590 119.350 ;
        RECT 71.840 117.270 84.720 117.280 ;
        RECT 71.810 116.850 84.720 117.270 ;
        RECT 71.810 116.810 72.060 116.850 ;
        RECT 84.470 116.820 84.720 116.850 ;
        RECT 87.730 116.455 109.000 116.640 ;
        RECT 64.105 116.225 109.105 116.455 ;
        RECT 87.730 115.840 109.000 116.225 ;
        RECT 71.780 115.445 85.990 115.680 ;
        RECT 109.305 115.495 109.535 116.175 ;
        RECT 64.105 115.215 109.105 115.445 ;
        RECT 71.780 114.900 85.990 115.215 ;
        RECT 87.790 114.435 108.740 114.790 ;
        RECT 109.305 114.485 109.535 115.165 ;
        RECT 64.105 114.205 109.105 114.435 ;
        RECT 87.790 113.850 108.740 114.205 ;
        RECT 64.730 113.425 86.010 113.850 ;
        RECT 109.305 113.475 109.535 114.155 ;
        RECT 64.105 113.205 109.105 113.425 ;
        RECT 64.730 112.840 86.010 113.205 ;
        RECT 87.810 112.425 108.760 112.730 ;
        RECT 109.305 112.475 109.535 113.155 ;
        RECT 64.105 112.195 109.105 112.425 ;
        RECT 87.810 111.790 108.760 112.195 ;
        RECT 64.680 111.415 85.960 111.760 ;
        RECT 109.305 111.465 109.535 112.145 ;
        RECT 64.105 111.185 109.105 111.415 ;
        RECT 64.680 110.750 85.960 111.185 ;
        RECT 87.810 110.405 108.860 110.780 ;
        RECT 109.305 110.455 109.535 111.135 ;
        RECT 64.105 110.175 109.105 110.405 ;
        RECT 87.810 109.980 108.860 110.175 ;
        RECT 111.740 110.060 112.610 116.450 ;
        RECT 48.580 100.670 49.320 100.680 ;
        RECT 48.710 100.490 49.320 100.670 ;
        RECT 48.710 99.910 52.650 100.490 ;
        RECT 48.720 99.870 52.650 99.910 ;
        RECT 48.720 99.840 50.010 99.870 ;
        RECT 48.870 99.820 50.010 99.840 ;
        RECT 52.360 97.770 52.630 99.870 ;
        RECT 59.300 99.780 62.680 101.310 ;
        RECT 53.700 99.680 68.000 99.780 ;
        RECT 53.700 99.490 59.710 99.680 ;
        RECT 62.040 99.490 68.050 99.680 ;
        RECT 53.700 99.430 59.700 99.490 ;
        RECT 62.050 99.450 68.050 99.490 ;
        RECT 53.250 99.020 53.550 99.420 ;
        RECT 59.850 99.280 61.890 99.430 ;
        RECT 68.210 99.280 68.440 99.400 ;
        RECT 56.860 99.010 58.400 99.150 ;
        RECT 59.850 99.050 68.440 99.280 ;
        RECT 53.700 98.780 59.700 99.010 ;
        RECT 61.600 98.810 68.440 99.050 ;
        RECT 62.050 98.800 68.050 98.810 ;
        RECT 56.860 98.710 58.400 98.780 ;
        RECT 63.500 98.650 65.000 98.800 ;
        RECT 62.420 97.770 62.840 97.790 ;
        RECT 45.155 97.210 46.455 97.545 ;
        RECT 49.785 97.210 51.085 97.605 ;
        RECT 52.360 97.540 62.840 97.770 ;
        RECT 45.155 96.850 55.140 97.210 ;
        RECT 57.180 96.850 59.500 96.870 ;
        RECT 45.155 96.650 59.500 96.850 ;
        RECT 45.155 95.780 55.140 96.650 ;
        RECT 57.180 96.630 59.500 96.650 ;
        RECT 62.420 96.810 62.840 97.540 ;
        RECT 62.420 96.570 64.750 96.810 ;
        RECT 62.450 96.565 62.770 96.570 ;
        RECT 63.100 96.565 63.420 96.570 ;
        RECT 63.740 96.565 64.060 96.570 ;
        RECT 64.390 96.565 64.710 96.570 ;
        RECT 56.915 96.370 57.145 96.435 ;
        RECT 45.155 95.445 46.455 95.780 ;
        RECT 49.785 95.505 51.085 95.780 ;
        RECT 49.670 87.780 51.160 92.970 ;
        RECT 49.670 85.580 51.180 87.780 ;
        RECT 49.670 85.560 51.160 85.580 ;
        RECT 56.820 64.640 57.250 96.370 ;
        RECT 56.915 60.435 57.145 64.640 ;
        RECT 57.565 64.350 57.795 96.435 ;
        RECT 58.215 96.430 58.435 96.435 ;
        RECT 58.070 64.700 58.500 96.430 ;
        RECT 57.460 62.320 57.920 64.350 ;
        RECT 57.565 61.890 57.795 62.320 ;
        RECT 57.500 60.620 57.870 61.890 ;
        RECT 57.565 60.435 57.795 60.620 ;
        RECT 58.215 60.435 58.435 64.700 ;
        RECT 58.855 64.350 59.085 96.435 ;
        RECT 59.440 96.150 59.810 96.460 ;
        RECT 62.170 96.300 62.400 96.365 ;
        RECT 59.440 64.680 59.790 96.150 ;
        RECT 58.720 62.320 59.180 64.350 ;
        RECT 58.855 60.435 59.085 62.320 ;
        RECT 59.505 60.435 59.735 64.680 ;
        RECT 62.120 64.650 62.560 96.300 ;
        RECT 60.110 60.450 61.780 61.440 ;
        RECT 62.170 60.365 62.400 64.650 ;
        RECT 62.820 64.360 63.050 96.365 ;
        RECT 63.470 96.330 63.690 96.365 ;
        RECT 63.410 64.600 63.840 96.330 ;
        RECT 62.650 62.170 63.180 64.360 ;
        RECT 62.820 60.365 63.050 62.170 ;
        RECT 63.470 60.365 63.690 64.600 ;
        RECT 64.110 64.320 64.340 96.365 ;
        RECT 64.760 96.330 64.990 96.365 ;
        RECT 64.620 64.600 65.050 96.330 ;
        RECT 63.970 62.200 64.470 64.320 ;
        RECT 64.110 60.365 64.340 62.200 ;
        RECT 64.760 60.365 64.990 64.600 ;
        RECT 57.195 60.230 57.515 60.235 ;
        RECT 57.845 60.230 58.165 60.235 ;
        RECT 58.485 60.230 58.805 60.235 ;
        RECT 59.135 60.230 59.455 60.235 ;
        RECT 57.180 60.010 59.480 60.230 ;
        RECT 62.450 60.140 62.770 60.165 ;
        RECT 63.100 60.140 63.420 60.165 ;
        RECT 63.740 60.140 64.060 60.165 ;
        RECT 64.390 60.140 64.710 60.165 ;
        RECT 57.195 60.005 57.515 60.010 ;
        RECT 57.845 60.005 58.165 60.010 ;
        RECT 58.485 60.005 58.805 60.010 ;
        RECT 59.135 60.005 59.455 60.010 ;
        RECT 62.440 59.920 64.750 60.140 ;
        RECT 57.600 59.290 58.560 59.450 ;
        RECT 57.600 59.280 68.470 59.290 ;
        RECT 57.600 59.275 102.140 59.280 ;
        RECT 57.600 59.270 102.350 59.275 ;
        RECT 57.600 59.055 102.490 59.270 ;
        RECT 57.600 59.040 68.470 59.055 ;
        RECT 57.600 58.960 58.560 59.040 ;
        RECT 59.120 57.930 62.900 58.870 ;
        RECT 59.130 57.265 62.890 57.420 ;
        RECT 54.995 57.035 84.995 57.265 ;
        RECT 54.410 56.985 54.790 56.990 ;
        RECT 54.410 56.305 54.795 56.985 ;
        RECT 59.130 56.790 62.890 57.035 ;
        RECT 54.410 55.975 54.790 56.305 ;
        RECT 70.030 56.255 84.800 56.580 ;
        RECT 85.195 56.305 85.425 56.985 ;
        RECT 54.995 56.025 84.995 56.255 ;
        RECT 54.410 55.295 54.795 55.975 ;
        RECT 70.030 55.680 84.800 56.025 ;
        RECT 54.410 54.965 54.790 55.295 ;
        RECT 55.190 55.245 69.340 55.490 ;
        RECT 85.195 55.295 85.425 55.975 ;
        RECT 54.995 55.015 84.995 55.245 ;
        RECT 54.410 54.285 54.795 54.965 ;
        RECT 55.190 54.760 69.340 55.015 ;
        RECT 54.410 53.955 54.790 54.285 ;
        RECT 70.020 54.235 84.810 54.590 ;
        RECT 85.195 54.285 85.425 54.965 ;
        RECT 54.995 54.005 84.995 54.235 ;
        RECT 54.410 53.275 54.795 53.955 ;
        RECT 70.020 53.720 84.810 54.005 ;
        RECT 54.410 52.955 54.790 53.275 ;
        RECT 55.210 53.225 69.360 53.470 ;
        RECT 85.195 53.275 85.425 53.955 ;
        RECT 54.995 53.005 84.995 53.225 ;
        RECT 54.410 52.275 54.795 52.955 ;
        RECT 55.210 52.740 69.360 53.005 ;
        RECT 54.410 51.945 54.790 52.275 ;
        RECT 70.000 52.225 84.830 52.570 ;
        RECT 85.195 52.275 85.425 52.955 ;
        RECT 54.995 51.995 84.995 52.225 ;
        RECT 54.410 51.265 54.795 51.945 ;
        RECT 70.000 51.750 84.830 51.995 ;
        RECT 54.410 50.935 54.790 51.265 ;
        RECT 55.190 51.215 69.340 51.430 ;
        RECT 85.195 51.265 85.425 51.945 ;
        RECT 54.995 50.985 84.995 51.215 ;
        RECT 54.410 50.255 54.795 50.935 ;
        RECT 55.190 50.700 69.340 50.985 ;
        RECT 54.410 49.925 54.790 50.255 ;
        RECT 70.020 50.205 84.850 50.450 ;
        RECT 85.195 50.255 85.425 50.935 ;
        RECT 88.350 50.420 94.300 53.850 ;
        RECT 102.285 51.910 102.490 59.055 ;
        RECT 54.995 49.975 84.995 50.205 ;
        RECT 54.410 49.245 54.795 49.925 ;
        RECT 70.020 49.630 84.850 49.975 ;
        RECT 54.410 46.330 54.790 49.245 ;
        RECT 55.210 49.195 69.360 49.560 ;
        RECT 85.195 49.245 85.425 49.925 ;
        RECT 88.395 49.875 94.075 50.420 ;
        RECT 102.295 49.330 102.480 51.910 ;
        RECT 54.995 48.965 84.995 49.195 ;
        RECT 55.210 48.830 69.360 48.965 ;
        RECT 71.810 48.010 84.810 48.590 ;
        RECT 63.060 46.330 69.580 46.350 ;
        RECT 54.410 46.275 69.580 46.330 ;
        RECT 54.410 46.045 69.870 46.275 ;
        RECT 54.410 43.720 69.580 46.045 ;
        RECT 69.940 45.845 70.470 45.860 ;
        RECT 54.410 43.680 54.790 43.720 ;
        RECT 63.060 42.645 69.580 43.720 ;
        RECT 69.920 42.860 70.470 45.845 ;
        RECT 69.920 42.845 70.150 42.860 ;
        RECT 63.060 42.415 69.870 42.645 ;
        RECT 63.060 42.380 69.580 42.415 ;
        RECT 63.520 32.940 63.950 42.380 ;
        RECT 88.395 42.155 94.075 44.195 ;
        RECT 102.300 43.500 102.475 49.330 ;
        RECT 122.560 44.720 124.870 47.275 ;
        RECT 103.000 43.755 112.750 44.070 ;
        RECT 102.840 43.525 120.840 43.755 ;
        RECT 103.040 43.520 112.760 43.525 ;
        RECT 102.300 42.480 102.700 43.500 ;
        RECT 103.050 43.420 112.760 43.520 ;
        RECT 113.110 43.105 120.790 43.270 ;
        RECT 102.840 42.885 120.840 43.105 ;
        RECT 113.110 42.730 120.790 42.885 ;
        RECT 102.300 42.475 102.475 42.480 ;
        RECT 103.140 42.465 112.680 42.630 ;
        RECT 102.840 42.235 120.840 42.465 ;
        RECT 120.980 42.410 124.870 44.720 ;
        RECT 120.990 42.380 121.480 42.410 ;
        RECT 103.140 42.120 112.680 42.235 ;
        RECT 113.160 41.440 120.910 41.890 ;
        RECT 71.800 39.350 84.800 39.930 ;
        RECT 87.750 39.045 109.020 39.220 ;
        RECT 64.125 38.815 109.125 39.045 ;
        RECT 87.750 38.450 109.020 38.815 ;
        RECT 64.840 38.035 86.060 38.270 ;
        RECT 109.325 38.085 109.555 38.765 ;
        RECT 64.125 37.805 109.125 38.035 ;
        RECT 64.840 37.440 86.060 37.805 ;
        RECT 87.720 37.025 108.780 37.350 ;
        RECT 109.325 37.075 109.555 37.755 ;
        RECT 64.125 36.795 109.125 37.025 ;
        RECT 87.720 36.460 108.780 36.795 ;
        RECT 64.710 36.015 86.070 36.330 ;
        RECT 109.325 36.065 109.555 36.745 ;
        RECT 64.125 35.795 109.125 36.015 ;
        RECT 64.710 35.530 86.070 35.795 ;
        RECT 87.740 35.015 108.800 35.300 ;
        RECT 109.325 35.065 109.555 35.745 ;
        RECT 64.125 34.785 109.125 35.015 ;
        RECT 87.740 34.410 108.800 34.785 ;
        RECT 64.710 34.005 86.070 34.310 ;
        RECT 109.325 34.055 109.555 34.735 ;
        RECT 64.125 33.775 109.125 34.005 ;
        RECT 64.710 33.510 86.070 33.775 ;
        RECT 87.770 32.995 108.850 33.390 ;
        RECT 109.325 33.045 109.555 33.725 ;
        RECT 64.125 32.765 109.125 32.995 ;
        RECT 87.770 32.630 108.850 32.765 ;
        RECT 87.820 32.610 108.820 32.630 ;
        RECT 111.555 23.490 113.440 40.030 ;
        RECT 111.600 22.865 113.440 23.490 ;
        RECT 111.600 20.955 119.690 22.865 ;
        RECT 111.600 20.930 113.370 20.955 ;
        RECT 50.100 20.180 52.100 20.600 ;
        RECT 58.490 19.910 117.520 20.000 ;
        RECT 29.180 19.730 29.350 19.800 ;
        RECT 29.120 14.590 29.440 19.730 ;
        RECT 29.580 19.680 117.580 19.910 ;
        RECT 58.490 19.620 117.520 19.680 ;
        RECT 50.100 19.430 52.120 19.520 ;
        RECT 29.580 19.200 117.580 19.430 ;
        RECT 50.100 19.130 52.120 19.200 ;
        RECT 44.080 18.950 46.800 19.000 ;
        RECT 58.480 18.950 117.460 19.020 ;
        RECT 29.580 18.720 117.580 18.950 ;
        RECT 44.080 18.660 46.800 18.720 ;
        RECT 58.480 18.640 117.460 18.720 ;
        RECT 50.100 18.470 52.120 18.580 ;
        RECT 29.580 18.240 117.580 18.470 ;
        RECT 50.100 18.170 52.120 18.240 ;
        RECT 44.140 17.990 46.800 18.070 ;
        RECT 58.480 17.990 117.460 18.080 ;
        RECT 29.580 17.760 117.580 17.990 ;
        RECT 44.140 17.740 46.800 17.760 ;
        RECT 58.480 17.700 117.460 17.760 ;
        RECT 50.110 17.510 52.190 17.620 ;
        RECT 29.580 17.280 117.580 17.510 ;
        RECT 50.110 17.230 52.190 17.280 ;
        RECT 44.130 17.030 46.800 17.120 ;
        RECT 58.480 17.030 117.460 17.130 ;
        RECT 29.580 16.810 117.580 17.030 ;
        RECT 44.130 16.760 46.800 16.810 ;
        RECT 58.480 16.750 117.460 16.810 ;
        RECT 50.110 16.560 52.190 16.660 ;
        RECT 29.580 16.330 117.580 16.560 ;
        RECT 50.110 16.250 52.190 16.330 ;
        RECT 44.140 16.080 46.810 16.160 ;
        RECT 58.480 16.080 117.460 16.170 ;
        RECT 29.580 15.850 117.580 16.080 ;
        RECT 44.140 15.800 46.810 15.850 ;
        RECT 58.480 15.790 117.460 15.850 ;
        RECT 50.060 15.600 52.140 15.700 ;
        RECT 29.580 15.370 117.580 15.600 ;
        RECT 50.060 15.290 52.140 15.370 ;
        RECT 44.140 15.120 46.810 15.200 ;
        RECT 58.480 15.120 117.460 15.210 ;
        RECT 29.580 14.890 117.580 15.120 ;
        RECT 44.140 14.840 46.810 14.890 ;
        RECT 58.480 14.830 117.460 14.890 ;
        RECT 50.040 14.640 52.120 14.740 ;
        RECT 29.180 14.430 29.350 14.590 ;
        RECT 29.150 14.140 29.380 14.430 ;
        RECT 29.580 14.410 117.580 14.640 ;
        RECT 50.040 14.330 52.120 14.410 ;
        RECT 44.130 14.160 46.800 14.250 ;
        RECT 58.480 14.160 117.460 14.260 ;
        RECT 29.180 14.040 29.350 14.140 ;
        RECT 29.580 13.930 117.580 14.160 ;
        RECT 44.130 13.890 46.800 13.930 ;
        RECT 58.480 13.880 117.460 13.930 ;
        RECT 117.780 13.870 119.690 20.955 ;
      LAYER met2 ;
        RECT 129.670 204.390 132.190 211.810 ;
        RECT 45.320 180.265 48.755 190.295 ;
        RECT 60.700 185.520 63.460 191.930 ;
        RECT 50.610 177.480 51.360 183.050 ;
        RECT 74.920 180.770 76.610 182.400 ;
        RECT 50.130 174.600 51.670 177.480 ;
        RECT 56.770 174.560 58.510 175.860 ;
        RECT 63.370 174.790 65.100 175.940 ;
        RECT 63.360 174.740 65.100 174.790 ;
        RECT 56.780 173.750 58.490 174.560 ;
        RECT 56.780 171.490 59.790 173.750 ;
        RECT 63.360 173.740 65.080 174.740 ;
        RECT 54.770 168.340 59.790 171.490 ;
        RECT 50.510 153.370 51.320 153.960 ;
        RECT 48.765 151.860 51.320 153.370 ;
        RECT 48.765 151.845 50.400 151.860 ;
        RECT 48.765 149.740 50.290 151.845 ;
        RECT 48.710 149.630 50.390 149.740 ;
        RECT 48.710 123.320 51.600 149.630 ;
        RECT 52.520 149.550 55.400 150.550 ;
        RECT 56.780 142.270 59.790 168.340 ;
        RECT 56.780 142.050 58.490 142.270 ;
        RECT 62.150 142.010 65.080 173.740 ;
        RECT 74.250 169.910 75.920 169.920 ;
        RECT 74.250 164.195 77.250 169.910 ;
        RECT 89.560 168.300 92.700 171.490 ;
        RECT 70.915 162.120 77.250 164.195 ;
        RECT 69.310 149.610 73.170 150.590 ;
        RECT 74.250 142.880 77.250 162.120 ;
        RECT 74.250 142.870 75.920 142.880 ;
        RECT 74.860 142.580 76.730 142.620 ;
        RECT 63.360 141.990 65.080 142.010 ;
        RECT 57.430 141.680 64.450 141.730 ;
        RECT 57.420 139.640 64.450 141.680 ;
        RECT 57.930 139.350 59.170 139.390 ;
        RECT 57.380 138.190 59.170 139.350 ;
        RECT 57.380 137.930 59.100 138.190 ;
        RECT 57.420 137.910 57.820 137.930 ;
        RECT 52.470 135.470 54.750 136.660 ;
        RECT 59.840 136.240 62.100 139.640 ;
        RECT 62.680 139.590 64.450 139.640 ;
        RECT 74.520 140.520 76.730 142.580 ;
        RECT 74.520 137.100 76.720 140.520 ;
        RECT 86.440 139.970 87.380 140.450 ;
        RECT 86.570 138.150 87.370 139.970 ;
        RECT 48.710 122.410 50.390 123.320 ;
        RECT 49.300 122.000 51.060 122.040 ;
        RECT 49.300 120.360 51.580 122.000 ;
        RECT 50.570 116.420 51.580 120.360 ;
        RECT 52.510 116.420 53.580 135.470 ;
        RECT 59.100 134.790 62.870 136.240 ;
        RECT 73.640 135.630 76.720 137.100 ;
        RECT 73.640 135.500 76.440 135.630 ;
        RECT 55.160 133.420 69.320 134.790 ;
        RECT 55.190 132.900 69.320 133.420 ;
        RECT 55.170 132.620 69.320 132.900 ;
        RECT 55.160 126.700 69.320 132.620 ;
        RECT 55.160 126.410 69.300 126.700 ;
        RECT 69.980 126.440 84.840 134.590 ;
        RECT 55.170 126.280 69.300 126.410 ;
        RECT 54.360 121.110 58.240 123.410 ;
        RECT 71.790 123.290 84.800 126.440 ;
        RECT 69.960 120.240 84.800 123.290 ;
        RECT 86.600 121.700 87.370 138.150 ;
        RECT 88.610 129.940 94.020 132.050 ;
        RECT 92.655 121.860 103.075 121.865 ;
        RECT 86.600 121.575 91.100 121.700 ;
        RECT 92.655 121.575 112.730 121.860 ;
        RECT 86.600 120.720 112.730 121.575 ;
        RECT 127.470 121.330 128.220 187.610 ;
        RECT 71.790 118.340 84.800 120.240 ;
        RECT 86.650 119.480 112.730 120.720 ;
        RECT 113.090 120.620 120.590 120.680 ;
        RECT 113.090 119.550 120.610 120.620 ;
        RECT 71.810 116.480 84.720 118.340 ;
        RECT 88.360 118.240 94.000 119.480 ;
        RECT 113.070 118.870 120.610 119.550 ;
        RECT 130.090 118.870 131.950 120.670 ;
        RECT 88.365 116.640 94.000 118.240 ;
        RECT 113.060 118.780 131.950 118.870 ;
        RECT 113.060 117.970 131.930 118.780 ;
        RECT 50.270 116.380 65.590 116.420 ;
        RECT 71.790 116.380 84.800 116.480 ;
        RECT 87.730 116.450 109.000 116.640 ;
        RECT 87.730 116.420 109.030 116.450 ;
        RECT 50.270 110.110 86.020 116.380 ;
        RECT 87.730 115.840 112.460 116.420 ;
        RECT 87.740 110.120 112.460 115.840 ;
        RECT 64.780 110.090 86.020 110.110 ;
        RECT 59.330 100.360 62.620 101.270 ;
        RECT 56.900 98.895 58.390 99.150 ;
        RECT 56.900 98.010 58.395 98.895 ;
        RECT 56.800 96.420 58.510 98.010 ;
        RECT 63.510 97.890 65.000 99.130 ;
        RECT 59.440 96.420 59.810 96.460 ;
        RECT 56.800 96.170 59.810 96.420 ;
        RECT 63.380 96.300 65.100 97.890 ;
        RECT 44.120 85.190 51.380 87.880 ;
        RECT 44.135 13.350 46.800 85.190 ;
        RECT 56.800 65.330 59.780 96.170 ;
        RECT 54.370 65.310 59.780 65.330 ;
        RECT 53.870 64.650 59.780 65.310 ;
        RECT 53.870 64.640 58.510 64.650 ;
        RECT 53.870 64.630 58.220 64.640 ;
        RECT 62.140 64.630 65.100 96.300 ;
        RECT 53.870 64.610 57.720 64.630 ;
        RECT 53.870 59.375 54.570 64.610 ;
        RECT 63.380 64.580 65.100 64.630 ;
        RECT 57.450 64.290 59.190 64.360 ;
        RECT 62.700 64.290 64.470 64.320 ;
        RECT 57.420 62.180 64.470 64.290 ;
        RECT 60.100 61.920 61.780 62.180 ;
        RECT 57.480 60.610 61.780 61.920 ;
        RECT 57.600 59.375 58.560 59.450 ;
        RECT 53.870 59.140 58.560 59.375 ;
        RECT 54.065 59.065 58.560 59.140 ;
        RECT 57.600 58.960 58.560 59.065 ;
        RECT 60.100 58.930 61.780 60.610 ;
        RECT 59.140 58.000 62.890 58.930 ;
        RECT 59.120 55.490 62.890 58.000 ;
        RECT 55.190 55.210 69.340 55.490 ;
        RECT 55.180 49.290 69.340 55.210 ;
        RECT 55.180 49.000 69.320 49.290 ;
        RECT 70.000 49.030 84.860 57.180 ;
        RECT 88.350 50.420 94.300 53.850 ;
        RECT 88.780 50.380 93.990 50.420 ;
        RECT 55.190 48.870 69.320 49.000 ;
        RECT 71.810 45.880 84.820 49.030 ;
        RECT 58.960 45.690 63.650 45.770 ;
        RECT 54.380 43.930 63.650 45.690 ;
        RECT 54.380 43.860 63.640 43.930 ;
        RECT 69.980 42.830 84.820 45.880 ;
        RECT 122.560 44.965 124.870 47.275 ;
        RECT 92.675 44.450 103.095 44.455 ;
        RECT 92.675 44.165 112.750 44.450 ;
        RECT 71.810 41.330 84.820 42.830 ;
        RECT 71.530 39.160 84.820 41.330 ;
        RECT 88.380 42.070 112.750 44.165 ;
        RECT 88.380 40.830 94.020 42.070 ;
        RECT 113.120 42.050 120.780 43.260 ;
        RECT 113.120 41.930 120.900 42.050 ;
        RECT 113.120 40.860 132.080 41.930 ;
        RECT 88.385 39.220 94.020 40.830 ;
        RECT 71.530 39.150 84.830 39.160 ;
        RECT 49.950 38.850 66.970 39.060 ;
        RECT 71.530 38.850 85.210 39.150 ;
        RECT 87.750 39.070 109.020 39.220 ;
        RECT 87.500 39.010 112.210 39.070 ;
        RECT 87.500 39.000 113.220 39.010 ;
        RECT 49.950 32.830 86.040 38.850 ;
        RECT 64.800 32.680 86.040 32.830 ;
        RECT 87.500 32.720 113.290 39.000 ;
        RECT 87.500 32.710 112.480 32.720 ;
        RECT 87.500 32.700 112.210 32.710 ;
        RECT 50.100 20.180 52.100 20.600 ;
        RECT 50.100 19.130 52.120 19.520 ;
        RECT 58.480 19.250 117.530 20.100 ;
        RECT 151.150 19.250 156.510 19.280 ;
        RECT 50.100 18.170 52.120 18.580 ;
        RECT 50.110 17.230 52.190 17.620 ;
        RECT 50.110 16.250 52.190 16.660 ;
        RECT 50.060 15.290 52.140 15.700 ;
        RECT 50.040 14.330 52.120 14.740 ;
        RECT 58.480 13.890 156.510 19.250 ;
        RECT 58.480 13.870 114.720 13.890 ;
        RECT 147.670 6.100 156.510 13.890 ;
        RECT 147.640 1.720 156.550 6.100 ;
      LAYER met3 ;
        RECT 129.670 204.390 132.190 211.810 ;
        RECT 50.090 201.790 76.500 201.840 ;
        RECT 50.090 197.870 76.650 201.790 ;
        RECT 60.630 185.480 69.370 192.080 ;
        RECT 67.770 178.160 69.330 185.480 ;
        RECT 75.020 182.400 76.650 197.870 ;
        RECT 74.920 180.840 76.650 182.400 ;
        RECT 95.930 187.610 128.090 187.640 ;
        RECT 74.920 180.770 76.610 180.840 ;
        RECT 59.460 177.380 69.350 178.160 ;
        RECT 54.860 168.450 56.180 171.410 ;
        RECT 52.520 149.550 55.400 150.550 ;
        RECT 52.470 135.470 54.750 136.660 ;
        RECT 50.350 110.140 52.000 116.440 ;
        RECT 54.430 62.230 58.170 123.340 ;
        RECT 59.470 101.230 63.630 177.380 ;
        RECT 89.560 168.300 92.700 171.490 ;
        RECT 95.930 157.240 128.220 187.610 ;
        RECT 127.470 155.640 128.220 157.240 ;
        RECT 69.310 149.610 73.170 150.590 ;
        RECT 73.640 135.500 76.440 137.100 ;
        RECT 88.910 130.180 93.870 131.850 ;
        RECT 95.930 125.240 128.220 155.640 ;
        RECT 127.470 121.330 128.220 125.240 ;
        RECT 120.730 120.220 131.990 120.610 ;
        RECT 120.690 119.670 131.990 120.220 ;
        RECT 110.140 110.200 111.630 116.360 ;
        RECT 112.100 101.690 132.260 117.090 ;
        RECT 59.410 100.470 63.630 101.230 ;
        RECT 59.410 100.390 62.530 100.470 ;
        RECT 67.960 63.430 98.360 95.590 ;
        RECT 99.960 63.430 130.360 95.590 ;
        RECT 54.430 62.220 57.420 62.230 ;
        RECT 54.430 60.430 57.310 62.220 ;
        RECT 54.430 59.925 57.420 60.430 ;
        RECT 51.185 58.535 57.420 59.925 ;
        RECT 51.185 48.000 52.575 58.535 ;
        RECT 54.430 58.130 57.420 58.535 ;
        RECT 88.350 50.420 94.300 53.850 ;
        RECT 88.780 50.380 93.990 50.420 ;
        RECT 51.185 47.535 58.170 48.000 ;
        RECT 51.195 45.690 58.170 47.535 ;
        RECT 58.960 45.690 63.650 45.770 ;
        RECT 51.195 45.445 63.650 45.690 ;
        RECT 51.910 44.260 63.650 45.445 ;
        RECT 122.560 44.965 124.870 47.275 ;
        RECT 54.380 43.930 63.650 44.260 ;
        RECT 54.380 43.860 63.640 43.930 ;
        RECT 54.430 40.710 58.170 43.860 ;
        RECT 130.120 40.890 132.030 41.910 ;
        RECT 50.230 33.010 51.820 38.920 ;
        RECT 50.100 20.180 52.100 20.600 ;
        RECT 50.100 19.130 52.120 19.520 ;
        RECT 50.100 18.170 52.120 18.580 ;
        RECT 50.110 17.230 52.190 17.620 ;
        RECT 50.110 16.250 52.190 16.660 ;
        RECT 50.060 15.290 52.140 15.700 ;
        RECT 50.040 14.330 52.120 14.740 ;
        RECT 54.460 7.090 57.850 40.710 ;
        RECT 112.800 39.000 132.960 39.100 ;
        RECT 112.300 32.720 132.960 39.000 ;
        RECT 112.800 23.700 132.960 32.720 ;
        RECT 54.340 5.080 134.590 7.090 ;
        RECT 54.340 4.500 134.630 5.080 ;
        RECT 54.340 3.800 136.190 4.500 ;
        RECT 129.670 3.330 136.190 3.800 ;
        RECT 129.580 3.100 136.190 3.330 ;
        RECT 129.580 1.350 136.140 3.100 ;
        RECT 147.640 1.720 156.550 6.100 ;
      LAYER met4 ;
        RECT 129.610 204.340 134.120 212.200 ;
        RECT 110.870 187.240 111.390 188.440 ;
        RECT 54.760 171.500 69.260 171.530 ;
        RECT 54.760 171.490 81.110 171.500 ;
        RECT 54.760 170.740 92.690 171.490 ;
        RECT 54.760 170.010 74.970 170.740 ;
        RECT 75.440 170.010 92.690 170.740 ;
        RECT 54.760 168.340 92.690 170.010 ;
        RECT 67.910 168.310 92.690 168.340 ;
        RECT 79.490 168.300 92.690 168.310 ;
        RECT 96.330 157.630 125.930 187.240 ;
        RECT 110.870 155.250 111.390 157.630 ;
        RECT 52.520 149.540 73.220 150.690 ;
        RECT 73.640 136.660 76.440 137.100 ;
        RECT 52.470 135.500 76.440 136.660 ;
        RECT 52.470 135.470 54.750 135.500 ;
        RECT 89.950 131.550 91.510 131.580 ;
        RECT 91.810 131.550 92.900 131.580 ;
        RECT 89.950 130.460 92.910 131.550 ;
        RECT 89.980 130.440 92.910 130.460 ;
        RECT 90.990 124.090 91.510 130.440 ;
        RECT 96.330 125.640 125.930 155.250 ;
        RECT 110.870 124.090 111.390 125.640 ;
        RECT 127.570 124.440 128.090 188.440 ;
        RECT 90.990 123.570 111.390 124.090 ;
        RECT 130.040 119.540 134.120 120.970 ;
        RECT 112.120 116.380 112.600 117.030 ;
        RECT 110.130 110.060 112.600 116.380 ;
        RECT 112.120 101.750 112.600 110.060 ;
        RECT 114.260 109.930 131.860 116.690 ;
        RECT 114.260 109.540 134.120 109.930 ;
        RECT 114.260 102.090 131.860 109.540 ;
        RECT 68.360 80.650 97.970 95.190 ;
        RECT 100.350 80.650 129.960 95.190 ;
        RECT 66.250 80.130 131.160 80.650 ;
        RECT 66.250 62.205 66.770 80.130 ;
        RECT 68.360 65.590 97.970 80.130 ;
        RECT 100.350 65.590 129.960 80.130 ;
        RECT 67.160 63.430 131.160 63.950 ;
        RECT 88.780 62.205 93.990 62.310 ;
        RECT 66.250 61.695 93.990 62.205 ;
        RECT 66.250 61.690 66.770 61.695 ;
        RECT 88.780 53.850 93.990 61.695 ;
        RECT 88.350 50.420 94.300 53.850 ;
        RECT 122.550 44.950 124.880 63.430 ;
        RECT 130.080 40.740 134.120 42.170 ;
        RECT 112.820 23.760 113.300 39.040 ;
        RECT 114.960 31.530 132.560 38.700 ;
        RECT 114.960 31.010 134.120 31.530 ;
        RECT 114.960 24.100 132.560 31.010 ;
        RECT 129.540 1.260 136.140 3.930 ;
        RECT 147.640 1.720 156.550 6.100 ;
        RECT 150.510 1.700 153.940 1.720 ;
        RECT 132.010 1.210 134.650 1.260 ;
        RECT 132.470 1.000 133.410 1.210 ;
        RECT 132.470 0.960 132.490 1.000 ;
        RECT 133.390 0.960 133.410 1.000 ;
        RECT 151.800 1.000 152.710 1.700 ;
        RECT 151.800 0.940 151.810 1.000 ;
  END
END tt_um_c0d3d1_ldo
END LIBRARY

